One B-rep face of a CAD part: STEP entity #1980.
In plain terms, the planar face has unit normal (0, 1, 0).
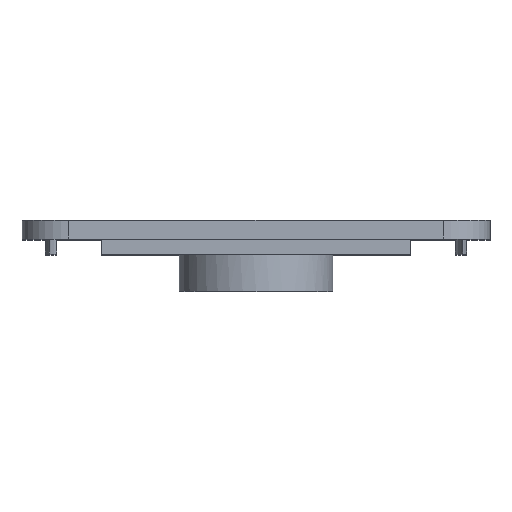
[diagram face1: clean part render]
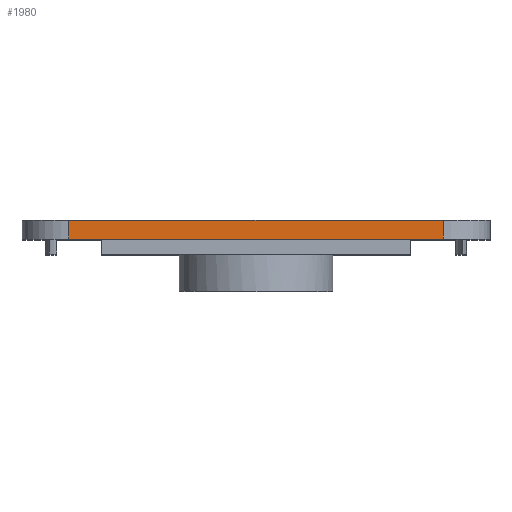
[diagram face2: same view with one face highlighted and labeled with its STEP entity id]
Its self-contained STEP definition (entity closure, numbers rounded to 3 decimals):
#90 = PLANE('',#91);
#91 = AXIS2_PLACEMENT_3D('',#92,#93,#94);
#92 = CARTESIAN_POINT('',(0.,0.,32.));
#93 = DIRECTION('',(0.,0.,1.));
#94 = DIRECTION('',(1.,0.,-0.));
#118 = CYLINDRICAL_SURFACE('',#119,5.);
#119 = AXIS2_PLACEMENT_3D('',#120,#121,#122);
#120 = CARTESIAN_POINT('',(-20.,29.,30.));
#121 = DIRECTION('',(0.,0.,-1.));
#122 = DIRECTION('',(-1.,0.,0.));
#144 = PLANE('',#145);
#145 = AXIS2_PLACEMENT_3D('',#146,#147,#148);
#146 = CARTESIAN_POINT('',(0.,0.,30.));
#147 = DIRECTION('',(0.,0.,1.));
#148 = DIRECTION('',(1.,0.,-0.));
#247 = VERTEX_POINT('',#248);
#248 = CARTESIAN_POINT('',(-20.,34.,32.));
#274 = EDGE_CURVE('',#275,#247,#277,.T.);
#275 = VERTEX_POINT('',#276);
#276 = CARTESIAN_POINT('',(-20.,34.,30.));
#277 = SURFACE_CURVE('',#278,(#282,#289),.PCURVE_S1.);
#278 = LINE('',#279,#280);
#279 = CARTESIAN_POINT('',(-20.,34.,30.));
#280 = VECTOR('',#281,1.);
#281 = DIRECTION('',(0.,0.,1.));
#282 = PCURVE('',#118,#283);
#283 = DEFINITIONAL_REPRESENTATION('',(#284),#288);
#284 = LINE('',#285,#286);
#285 = CARTESIAN_POINT('',(1.571,0.));
#286 = VECTOR('',#287,1.);
#287 = DIRECTION('',(0.,-1.));
#288 = ( GEOMETRIC_REPRESENTATION_CONTEXT(2) 
PARAMETRIC_REPRESENTATION_CONTEXT() REPRESENTATION_CONTEXT('2D SPACE',''
  ) );
#289 = PCURVE('',#290,#295);
#290 = PLANE('',#291);
#291 = AXIS2_PLACEMENT_3D('',#292,#293,#294);
#292 = CARTESIAN_POINT('',(-20.,34.,30.));
#293 = DIRECTION('',(0.,1.,0.));
#294 = DIRECTION('',(1.,0.,0.));
#295 = DEFINITIONAL_REPRESENTATION('',(#296),#300);
#296 = LINE('',#297,#298);
#297 = CARTESIAN_POINT('',(0.,0.));
#298 = VECTOR('',#299,1.);
#299 = DIRECTION('',(0.,-1.));
#300 = ( GEOMETRIC_REPRESENTATION_CONTEXT(2) 
PARAMETRIC_REPRESENTATION_CONTEXT() REPRESENTATION_CONTEXT('2D SPACE',''
  ) );
#418 = VERTEX_POINT('',#419);
#419 = CARTESIAN_POINT('',(20.,34.,30.));
#438 = CYLINDRICAL_SURFACE('',#439,5.);
#439 = AXIS2_PLACEMENT_3D('',#440,#441,#442);
#440 = CARTESIAN_POINT('',(20.,29.,30.));
#441 = DIRECTION('',(0.,0.,-1.));
#442 = DIRECTION('',(-1.,0.,0.));
#450 = EDGE_CURVE('',#275,#418,#451,.T.);
#451 = SURFACE_CURVE('',#452,(#456,#463),.PCURVE_S1.);
#452 = LINE('',#453,#454);
#453 = CARTESIAN_POINT('',(0.,34.,30.));
#454 = VECTOR('',#455,1.);
#455 = DIRECTION('',(1.,0.,0.));
#456 = PCURVE('',#144,#457);
#457 = DEFINITIONAL_REPRESENTATION('',(#458),#462);
#458 = LINE('',#459,#460);
#459 = CARTESIAN_POINT('',(0.,34.));
#460 = VECTOR('',#461,1.);
#461 = DIRECTION('',(1.,0.));
#462 = ( GEOMETRIC_REPRESENTATION_CONTEXT(2) 
PARAMETRIC_REPRESENTATION_CONTEXT() REPRESENTATION_CONTEXT('2D SPACE',''
  ) );
#463 = PCURVE('',#290,#464);
#464 = DEFINITIONAL_REPRESENTATION('',(#465),#469);
#465 = LINE('',#466,#467);
#466 = CARTESIAN_POINT('',(20.,0.));
#467 = VECTOR('',#468,1.);
#468 = DIRECTION('',(1.,0.));
#469 = ( GEOMETRIC_REPRESENTATION_CONTEXT(2) 
PARAMETRIC_REPRESENTATION_CONTEXT() REPRESENTATION_CONTEXT('2D SPACE',''
  ) );
#1564 = VERTEX_POINT('',#1565);
#1565 = CARTESIAN_POINT('',(20.,34.,32.));
#1591 = EDGE_CURVE('',#247,#1564,#1592,.T.);
#1592 = SURFACE_CURVE('',#1593,(#1597,#1604),.PCURVE_S1.);
#1593 = LINE('',#1594,#1595);
#1594 = CARTESIAN_POINT('',(0.,34.,32.));
#1595 = VECTOR('',#1596,1.);
#1596 = DIRECTION('',(1.,0.,0.));
#1597 = PCURVE('',#90,#1598);
#1598 = DEFINITIONAL_REPRESENTATION('',(#1599),#1603);
#1599 = LINE('',#1600,#1601);
#1600 = CARTESIAN_POINT('',(0.,34.));
#1601 = VECTOR('',#1602,1.);
#1602 = DIRECTION('',(1.,0.));
#1603 = ( GEOMETRIC_REPRESENTATION_CONTEXT(2) 
PARAMETRIC_REPRESENTATION_CONTEXT() REPRESENTATION_CONTEXT('2D SPACE',''
  ) );
#1604 = PCURVE('',#290,#1605);
#1605 = DEFINITIONAL_REPRESENTATION('',(#1606),#1610);
#1606 = LINE('',#1607,#1608);
#1607 = CARTESIAN_POINT('',(20.,-2.));
#1608 = VECTOR('',#1609,1.);
#1609 = DIRECTION('',(1.,0.));
#1610 = ( GEOMETRIC_REPRESENTATION_CONTEXT(2) 
PARAMETRIC_REPRESENTATION_CONTEXT() REPRESENTATION_CONTEXT('2D SPACE',''
  ) );
#1980 = ADVANCED_FACE('',(#1981),#290,.T.);
#1981 = FACE_BOUND('',#1982,.T.);
#1982 = EDGE_LOOP('',(#1983,#1984,#1985,#2006));
#1983 = ORIENTED_EDGE('',*,*,#274,.T.);
#1984 = ORIENTED_EDGE('',*,*,#1591,.T.);
#1985 = ORIENTED_EDGE('',*,*,#1986,.F.);
#1986 = EDGE_CURVE('',#418,#1564,#1987,.T.);
#1987 = SURFACE_CURVE('',#1988,(#1992,#1999),.PCURVE_S1.);
#1988 = LINE('',#1989,#1990);
#1989 = CARTESIAN_POINT('',(20.,34.,30.));
#1990 = VECTOR('',#1991,1.);
#1991 = DIRECTION('',(0.,0.,1.));
#1992 = PCURVE('',#290,#1993);
#1993 = DEFINITIONAL_REPRESENTATION('',(#1994),#1998);
#1994 = LINE('',#1995,#1996);
#1995 = CARTESIAN_POINT('',(40.,0.));
#1996 = VECTOR('',#1997,1.);
#1997 = DIRECTION('',(0.,-1.));
#1998 = ( GEOMETRIC_REPRESENTATION_CONTEXT(2) 
PARAMETRIC_REPRESENTATION_CONTEXT() REPRESENTATION_CONTEXT('2D SPACE',''
  ) );
#1999 = PCURVE('',#438,#2000);
#2000 = DEFINITIONAL_REPRESENTATION('',(#2001),#2005);
#2001 = LINE('',#2002,#2003);
#2002 = CARTESIAN_POINT('',(1.571,0.));
#2003 = VECTOR('',#2004,1.);
#2004 = DIRECTION('',(0.,-1.));
#2005 = ( GEOMETRIC_REPRESENTATION_CONTEXT(2) 
PARAMETRIC_REPRESENTATION_CONTEXT() REPRESENTATION_CONTEXT('2D SPACE',''
  ) );
#2006 = ORIENTED_EDGE('',*,*,#450,.F.);
